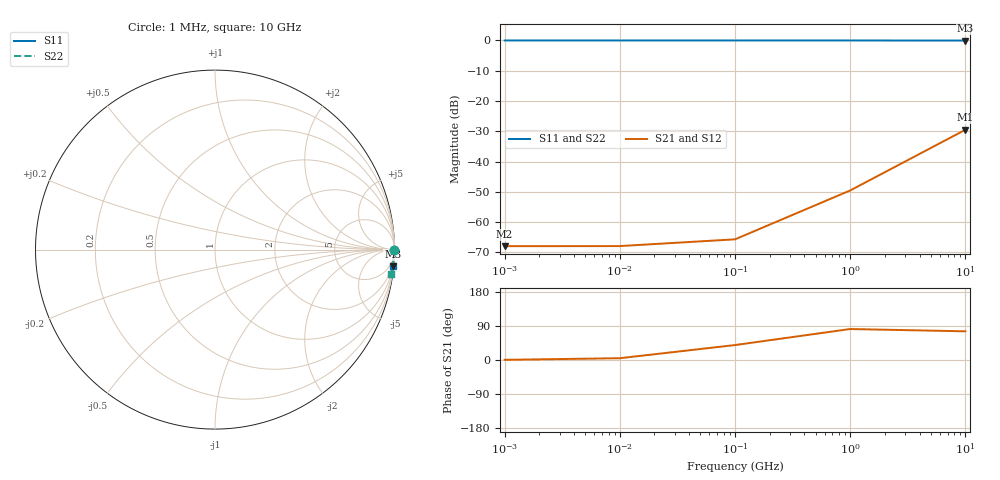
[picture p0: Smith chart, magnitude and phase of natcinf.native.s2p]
! Sonnet Data File
! From: em Version : 18.53-Lite
! From Project: natcinf
! Data is NOT De-embedded
! Data File Written: 10/12/2026 13:00:58
!< HDATE 10/12/2026 13:00:58
!< MDATE 10/12/2026 13:00:58
# GHZ S RI R 50.00000
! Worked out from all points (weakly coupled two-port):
!   5 points, 1 MHz to 10 GHz, reference 50 ohm
!   highest |S21| = -29.51 dB at 10 GHz (marker M1); lowest = -68.0 dB at 1 MHz (marker M2)
!   lowest |S11| = 0.0 dB at 10 GHz (marker M3), VSWR 356.93, Z = 63 - j1.06e+03 ohm
!   |S11| at or under -10 dB: nowhere
!   |S22| runs from -0.1 to 0.0 dB; largest |S21 - S12| = 2e-15
0.001  0.9996 -9.35e-06  0.0004 3.29e-06  0.0004 3.29e-06  0.9996 -1.35e-05
0.01  0.9996 -9.35e-05  0.0004 3.29e-05  0.0004 3.29e-05  0.9996 -0.000135
0.1  0.9996 -0.000935  0.0004 0.000329  0.0004 0.000329  0.9996 -0.00135
1  0.9995 -0.00935  0.000478 0.00329  0.000478 0.00329  0.9994 -0.0135
10  0.99 -0.0935  0.00828 0.0324  0.00828 0.0324  0.9817 -0.1341
